VERSION 5.8 ;
BUSBITCHARS "[]" ;
DIVIDERCHAR "/" ;
UNITS
    DATABASE MICRONS 1000 ;
END UNITS

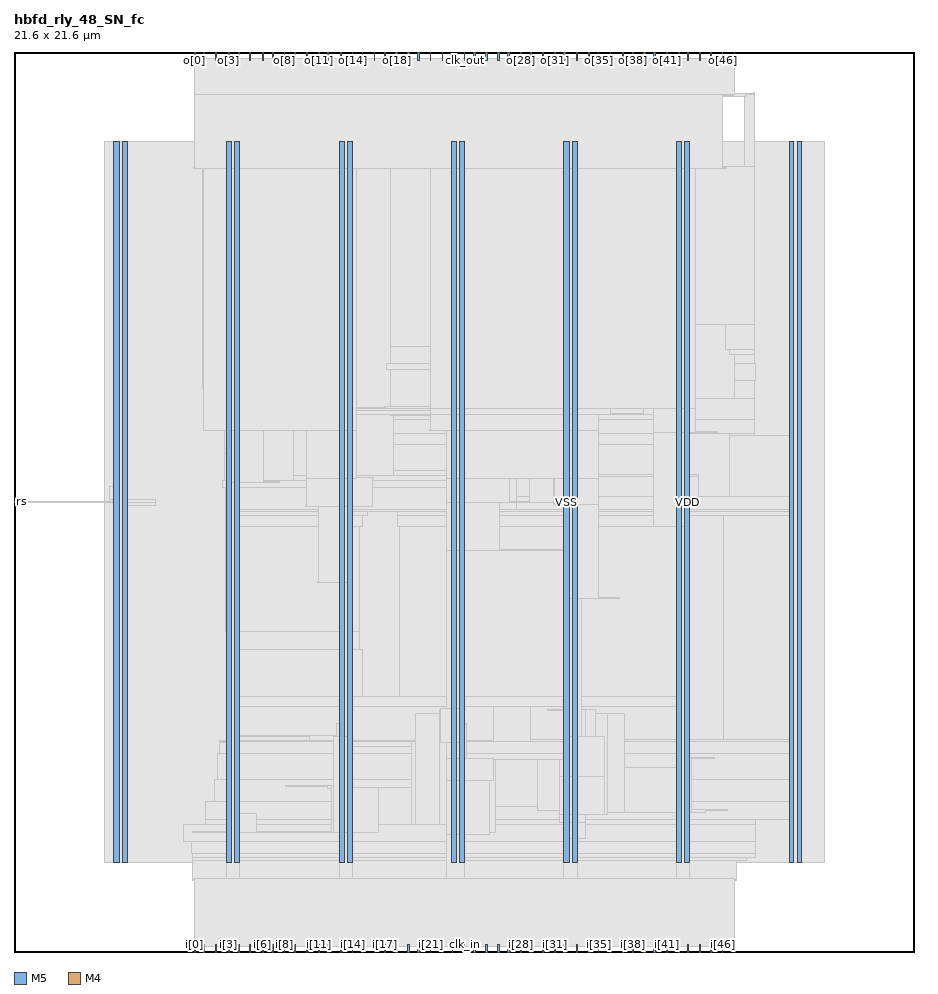
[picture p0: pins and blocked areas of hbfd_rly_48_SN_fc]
MACRO hbfd_rly_48_SN_fc
  FOREIGN hbfd_rly_48_SN_fc 0 0 ;
  CLASS BLOCK ;
  SIZE 21.6 BY 21.6 ;
  PIN clk_in
    DIRECTION INPUT ;
    USE SIGNAL ;
    PORT
      LAYER M5 ;
        RECT  10.8 0 10.824 0.192 ;
    END
  END clk_in
  PIN clk_out
    DIRECTION OUTPUT ;
    USE SIGNAL ;
    PORT
      LAYER M5 ;
        RECT  10.8 21.408 10.824 21.6 ;
    END
  END clk_out
  PIN i[0]
    DIRECTION INPUT ;
    USE SIGNAL ;
    PORT
      LAYER M5 ;
        RECT  4.32 0 4.344 0.192 ;
    END
  END i[0]
  PIN i[10]
    DIRECTION INPUT ;
    USE SIGNAL ;
    PORT
      LAYER M5 ;
        RECT  7.008 0 7.032 0.192 ;
    END
  END i[10]
  PIN i[11]
    DIRECTION INPUT ;
    USE SIGNAL ;
    PORT
      LAYER M5 ;
        RECT  7.296 0 7.32 0.192 ;
    END
  END i[11]
  PIN i[12]
    DIRECTION INPUT ;
    USE SIGNAL ;
    PORT
      LAYER M5 ;
        RECT  7.536 0 7.56 0.192 ;
    END
  END i[12]
  PIN i[13]
    DIRECTION INPUT ;
    USE SIGNAL ;
    PORT
      LAYER M5 ;
        RECT  7.824 0 7.848 0.192 ;
    END
  END i[13]
  PIN i[14]
    DIRECTION INPUT ;
    USE SIGNAL ;
    PORT
      LAYER M5 ;
        RECT  8.112 0 8.136 0.192 ;
    END
  END i[14]
  PIN i[15]
    DIRECTION INPUT ;
    USE SIGNAL ;
    PORT
      LAYER M5 ;
        RECT  8.352 0 8.376 0.192 ;
    END
  END i[15]
  PIN i[16]
    DIRECTION INPUT ;
    USE SIGNAL ;
    PORT
      LAYER M5 ;
        RECT  8.64 0 8.664 0.192 ;
    END
  END i[16]
  PIN i[17]
    DIRECTION INPUT ;
    USE SIGNAL ;
    PORT
      LAYER M5 ;
        RECT  8.88 0 8.904 0.192 ;
    END
  END i[17]
  PIN i[18]
    DIRECTION INPUT ;
    USE SIGNAL ;
    PORT
      LAYER M5 ;
        RECT  9.168 0 9.192 0.192 ;
    END
  END i[18]
  PIN i[19]
    DIRECTION INPUT ;
    USE SIGNAL ;
    PORT
      LAYER M5 ;
        RECT  9.456 0 9.48 0.192 ;
    END
  END i[19]
  PIN i[1]
    DIRECTION INPUT ;
    USE SIGNAL ;
    PORT
      LAYER M5 ;
        RECT  4.56 0 4.584 0.192 ;
    END
  END i[1]
  PIN i[20]
    DIRECTION INPUT ;
    USE SIGNAL ;
    PORT
      LAYER M5 ;
        RECT  9.696 0 9.72 0.192 ;
    END
  END i[20]
  PIN i[21]
    DIRECTION INPUT ;
    USE SIGNAL ;
    PORT
      LAYER M5 ;
        RECT  9.984 0 10.008 0.192 ;
    END
  END i[21]
  PIN i[22]
    DIRECTION INPUT ;
    USE SIGNAL ;
    PORT
      LAYER M5 ;
        RECT  10.272 0 10.296 0.192 ;
    END
  END i[22]
  PIN i[23]
    DIRECTION INPUT ;
    USE SIGNAL ;
    PORT
      LAYER M5 ;
        RECT  10.512 0 10.536 0.192 ;
    END
  END i[23]
  PIN i[24]
    DIRECTION INPUT ;
    USE SIGNAL ;
    PORT
      LAYER M5 ;
        RECT  11.04 0 11.064 0.192 ;
    END
  END i[24]
  PIN i[25]
    DIRECTION INPUT ;
    USE SIGNAL ;
    PORT
      LAYER M5 ;
        RECT  11.328 0 11.352 0.192 ;
    END
  END i[25]
  PIN i[26]
    DIRECTION INPUT ;
    USE SIGNAL ;
    PORT
      LAYER M5 ;
        RECT  11.616 0 11.64 0.192 ;
    END
  END i[26]
  PIN i[27]
    DIRECTION INPUT ;
    USE SIGNAL ;
    PORT
      LAYER M5 ;
        RECT  11.856 0 11.88 0.192 ;
    END
  END i[27]
  PIN i[28]
    DIRECTION INPUT ;
    USE SIGNAL ;
    PORT
      LAYER M5 ;
        RECT  12.144 0 12.168 0.192 ;
    END
  END i[28]
  PIN i[29]
    DIRECTION INPUT ;
    USE SIGNAL ;
    PORT
      LAYER M5 ;
        RECT  12.384 0 12.408 0.192 ;
    END
  END i[29]
  PIN i[2]
    DIRECTION INPUT ;
    USE SIGNAL ;
    PORT
      LAYER M5 ;
        RECT  4.848 0 4.872 0.192 ;
    END
  END i[2]
  PIN i[30]
    DIRECTION INPUT ;
    USE SIGNAL ;
    PORT
      LAYER M5 ;
        RECT  12.672 0 12.696 0.192 ;
    END
  END i[30]
  PIN i[31]
    DIRECTION INPUT ;
    USE SIGNAL ;
    PORT
      LAYER M5 ;
        RECT  12.96 0 12.984 0.192 ;
    END
  END i[31]
  PIN i[32]
    DIRECTION INPUT ;
    USE SIGNAL ;
    PORT
      LAYER M5 ;
        RECT  13.2 0 13.224 0.192 ;
    END
  END i[32]
  PIN i[33]
    DIRECTION INPUT ;
    USE SIGNAL ;
    PORT
      LAYER M5 ;
        RECT  13.488 0 13.512 0.192 ;
    END
  END i[33]
  PIN i[34]
    DIRECTION INPUT ;
    USE SIGNAL ;
    PORT
      LAYER M5 ;
        RECT  13.776 0 13.8 0.192 ;
    END
  END i[34]
  PIN i[35]
    DIRECTION INPUT ;
    USE SIGNAL ;
    PORT
      LAYER M5 ;
        RECT  14.016 0 14.04 0.192 ;
    END
  END i[35]
  PIN i[36]
    DIRECTION INPUT ;
    USE SIGNAL ;
    PORT
      LAYER M5 ;
        RECT  14.304 0 14.328 0.192 ;
    END
  END i[36]
  PIN i[37]
    DIRECTION INPUT ;
    USE SIGNAL ;
    PORT
      LAYER M5 ;
        RECT  14.592 0 14.616 0.192 ;
    END
  END i[37]
  PIN i[38]
    DIRECTION INPUT ;
    USE SIGNAL ;
    PORT
      LAYER M5 ;
        RECT  14.832 0 14.856 0.192 ;
    END
  END i[38]
  PIN i[39]
    DIRECTION INPUT ;
    USE SIGNAL ;
    PORT
      LAYER M5 ;
        RECT  15.12 0 15.144 0.192 ;
    END
  END i[39]
  PIN i[3]
    DIRECTION INPUT ;
    USE SIGNAL ;
    PORT
      LAYER M5 ;
        RECT  5.136 0 5.16 0.192 ;
    END
  END i[3]
  PIN i[40]
    DIRECTION INPUT ;
    USE SIGNAL ;
    PORT
      LAYER M5 ;
        RECT  15.36 0 15.384 0.192 ;
    END
  END i[40]
  PIN i[41]
    DIRECTION INPUT ;
    USE SIGNAL ;
    PORT
      LAYER M5 ;
        RECT  15.648 0 15.672 0.192 ;
    END
  END i[41]
  PIN i[42]
    DIRECTION INPUT ;
    USE SIGNAL ;
    PORT
      LAYER M5 ;
        RECT  15.936 0 15.96 0.192 ;
    END
  END i[42]
  PIN i[43]
    DIRECTION INPUT ;
    USE SIGNAL ;
    PORT
      LAYER M5 ;
        RECT  16.176 0 16.2 0.192 ;
    END
  END i[43]
  PIN i[44]
    DIRECTION INPUT ;
    USE SIGNAL ;
    PORT
      LAYER M5 ;
        RECT  16.464 0 16.488 0.192 ;
    END
  END i[44]
  PIN i[45]
    DIRECTION INPUT ;
    USE SIGNAL ;
    PORT
      LAYER M5 ;
        RECT  16.704 0 16.728 0.192 ;
    END
  END i[45]
  PIN i[46]
    DIRECTION INPUT ;
    USE SIGNAL ;
    PORT
      LAYER M5 ;
        RECT  16.992 0 17.016 0.192 ;
    END
  END i[46]
  PIN i[47]
    DIRECTION INPUT ;
    USE SIGNAL ;
    PORT
      LAYER M5 ;
        RECT  17.28 0 17.304 0.192 ;
    END
  END i[47]
  PIN i[4]
    DIRECTION INPUT ;
    USE SIGNAL ;
    PORT
      LAYER M5 ;
        RECT  5.376 0 5.4 0.192 ;
    END
  END i[4]
  PIN i[5]
    DIRECTION INPUT ;
    USE SIGNAL ;
    PORT
      LAYER M5 ;
        RECT  5.664 0 5.688 0.192 ;
    END
  END i[5]
  PIN i[6]
    DIRECTION INPUT ;
    USE SIGNAL ;
    PORT
      LAYER M5 ;
        RECT  5.952 0 5.976 0.192 ;
    END
  END i[6]
  PIN i[7]
    DIRECTION INPUT ;
    USE SIGNAL ;
    PORT
      LAYER M5 ;
        RECT  6.192 0 6.216 0.192 ;
    END
  END i[7]
  PIN i[8]
    DIRECTION INPUT ;
    USE SIGNAL ;
    PORT
      LAYER M5 ;
        RECT  6.48 0 6.504 0.192 ;
    END
  END i[8]
  PIN i[9]
    DIRECTION INPUT ;
    USE SIGNAL ;
    PORT
      LAYER M5 ;
        RECT  6.72 0 6.744 0.192 ;
    END
  END i[9]
  PIN o[0]
    DIRECTION OUTPUT ;
    USE SIGNAL ;
    PORT
      LAYER M5 ;
        RECT  4.32 21.408 4.344 21.6 ;
    END
  END o[0]
  PIN o[10]
    DIRECTION OUTPUT ;
    USE SIGNAL ;
    PORT
      LAYER M5 ;
        RECT  7.008 21.408 7.032 21.6 ;
    END
  END o[10]
  PIN o[11]
    DIRECTION OUTPUT ;
    USE SIGNAL ;
    PORT
      LAYER M5 ;
        RECT  7.296 21.408 7.32 21.6 ;
    END
  END o[11]
  PIN o[12]
    DIRECTION OUTPUT ;
    USE SIGNAL ;
    PORT
      LAYER M5 ;
        RECT  7.536 21.408 7.56 21.6 ;
    END
  END o[12]
  PIN o[13]
    DIRECTION OUTPUT ;
    USE SIGNAL ;
    PORT
      LAYER M5 ;
        RECT  7.824 21.408 7.848 21.6 ;
    END
  END o[13]
  PIN o[14]
    DIRECTION OUTPUT ;
    USE SIGNAL ;
    PORT
      LAYER M5 ;
        RECT  8.112 21.408 8.136 21.6 ;
    END
  END o[14]
  PIN o[15]
    DIRECTION OUTPUT ;
    USE SIGNAL ;
    PORT
      LAYER M5 ;
        RECT  8.352 21.408 8.376 21.6 ;
    END
  END o[15]
  PIN o[16]
    DIRECTION OUTPUT ;
    USE SIGNAL ;
    PORT
      LAYER M5 ;
        RECT  8.64 21.408 8.664 21.6 ;
    END
  END o[16]
  PIN o[17]
    DIRECTION OUTPUT ;
    USE SIGNAL ;
    PORT
      LAYER M5 ;
        RECT  8.88 21.408 8.904 21.6 ;
    END
  END o[17]
  PIN o[18]
    DIRECTION OUTPUT ;
    USE SIGNAL ;
    PORT
      LAYER M5 ;
        RECT  9.168 21.408 9.192 21.6 ;
    END
  END o[18]
  PIN o[19]
    DIRECTION OUTPUT ;
    USE SIGNAL ;
    PORT
      LAYER M5 ;
        RECT  9.456 21.408 9.48 21.6 ;
    END
  END o[19]
  PIN o[1]
    DIRECTION OUTPUT ;
    USE SIGNAL ;
    PORT
      LAYER M5 ;
        RECT  4.56 21.408 4.584 21.6 ;
    END
  END o[1]
  PIN o[20]
    DIRECTION OUTPUT ;
    USE SIGNAL ;
    PORT
      LAYER M5 ;
        RECT  9.696 21.408 9.72 21.6 ;
    END
  END o[20]
  PIN o[21]
    DIRECTION OUTPUT ;
    USE SIGNAL ;
    PORT
      LAYER M5 ;
        RECT  9.984 21.408 10.008 21.6 ;
    END
  END o[21]
  PIN o[22]
    DIRECTION OUTPUT ;
    USE SIGNAL ;
    PORT
      LAYER M5 ;
        RECT  10.272 21.408 10.296 21.6 ;
    END
  END o[22]
  PIN o[23]
    DIRECTION OUTPUT ;
    USE SIGNAL ;
    PORT
      LAYER M5 ;
        RECT  10.512 21.408 10.536 21.6 ;
    END
  END o[23]
  PIN o[24]
    DIRECTION OUTPUT ;
    USE SIGNAL ;
    PORT
      LAYER M5 ;
        RECT  11.04 21.408 11.064 21.6 ;
    END
  END o[24]
  PIN o[25]
    DIRECTION OUTPUT ;
    USE SIGNAL ;
    PORT
      LAYER M5 ;
        RECT  11.328 21.408 11.352 21.6 ;
    END
  END o[25]
  PIN o[26]
    DIRECTION OUTPUT ;
    USE SIGNAL ;
    PORT
      LAYER M5 ;
        RECT  11.616 21.408 11.64 21.6 ;
    END
  END o[26]
  PIN o[27]
    DIRECTION OUTPUT ;
    USE SIGNAL ;
    PORT
      LAYER M5 ;
        RECT  11.856 21.408 11.88 21.6 ;
    END
  END o[27]
  PIN o[28]
    DIRECTION OUTPUT ;
    USE SIGNAL ;
    PORT
      LAYER M5 ;
        RECT  12.144 21.408 12.168 21.6 ;
    END
  END o[28]
  PIN o[29]
    DIRECTION OUTPUT ;
    USE SIGNAL ;
    PORT
      LAYER M5 ;
        RECT  12.384 21.408 12.408 21.6 ;
    END
  END o[29]
  PIN o[2]
    DIRECTION OUTPUT ;
    USE SIGNAL ;
    PORT
      LAYER M5 ;
        RECT  4.848 21.408 4.872 21.6 ;
    END
  END o[2]
  PIN o[30]
    DIRECTION OUTPUT ;
    USE SIGNAL ;
    PORT
      LAYER M5 ;
        RECT  12.672 21.408 12.696 21.6 ;
    END
  END o[30]
  PIN o[31]
    DIRECTION OUTPUT ;
    USE SIGNAL ;
    PORT
      LAYER M5 ;
        RECT  12.96 21.408 12.984 21.6 ;
    END
  END o[31]
  PIN o[32]
    DIRECTION OUTPUT ;
    USE SIGNAL ;
    PORT
      LAYER M5 ;
        RECT  13.2 21.408 13.224 21.6 ;
    END
  END o[32]
  PIN o[33]
    DIRECTION OUTPUT ;
    USE SIGNAL ;
    PORT
      LAYER M5 ;
        RECT  13.488 21.408 13.512 21.6 ;
    END
  END o[33]
  PIN o[34]
    DIRECTION OUTPUT ;
    USE SIGNAL ;
    PORT
      LAYER M5 ;
        RECT  13.776 21.408 13.8 21.6 ;
    END
  END o[34]
  PIN o[35]
    DIRECTION OUTPUT ;
    USE SIGNAL ;
    PORT
      LAYER M5 ;
        RECT  14.016 21.408 14.04 21.6 ;
    END
  END o[35]
  PIN o[36]
    DIRECTION OUTPUT ;
    USE SIGNAL ;
    PORT
      LAYER M5 ;
        RECT  14.304 21.408 14.328 21.6 ;
    END
  END o[36]
  PIN o[37]
    DIRECTION OUTPUT ;
    USE SIGNAL ;
    PORT
      LAYER M5 ;
        RECT  14.592 21.408 14.616 21.6 ;
    END
  END o[37]
  PIN o[38]
    DIRECTION OUTPUT ;
    USE SIGNAL ;
    PORT
      LAYER M5 ;
        RECT  14.832 21.408 14.856 21.6 ;
    END
  END o[38]
  PIN o[39]
    DIRECTION OUTPUT ;
    USE SIGNAL ;
    PORT
      LAYER M5 ;
        RECT  15.12 21.408 15.144 21.6 ;
    END
  END o[39]
  PIN o[3]
    DIRECTION OUTPUT ;
    USE SIGNAL ;
    PORT
      LAYER M5 ;
        RECT  5.136 21.408 5.16 21.6 ;
    END
  END o[3]
  PIN o[40]
    DIRECTION OUTPUT ;
    USE SIGNAL ;
    PORT
      LAYER M5 ;
        RECT  15.36 21.408 15.384 21.6 ;
    END
  END o[40]
  PIN o[41]
    DIRECTION OUTPUT ;
    USE SIGNAL ;
    PORT
      LAYER M5 ;
        RECT  15.648 21.408 15.672 21.6 ;
    END
  END o[41]
  PIN o[42]
    DIRECTION OUTPUT ;
    USE SIGNAL ;
    PORT
      LAYER M5 ;
        RECT  15.936 21.408 15.96 21.6 ;
    END
  END o[42]
  PIN o[43]
    DIRECTION OUTPUT ;
    USE SIGNAL ;
    PORT
      LAYER M5 ;
        RECT  16.176 21.408 16.2 21.6 ;
    END
  END o[43]
  PIN o[44]
    DIRECTION OUTPUT ;
    USE SIGNAL ;
    PORT
      LAYER M5 ;
        RECT  16.464 21.408 16.488 21.6 ;
    END
  END o[44]
  PIN o[45]
    DIRECTION OUTPUT ;
    USE SIGNAL ;
    PORT
      LAYER M5 ;
        RECT  16.704 21.408 16.728 21.6 ;
    END
  END o[45]
  PIN o[46]
    DIRECTION OUTPUT ;
    USE SIGNAL ;
    PORT
      LAYER M5 ;
        RECT  16.992 21.408 17.016 21.6 ;
    END
  END o[46]
  PIN o[47]
    DIRECTION OUTPUT ;
    USE SIGNAL ;
    PORT
      LAYER M5 ;
        RECT  17.28 21.408 17.304 21.6 ;
    END
  END o[47]
  PIN o[4]
    DIRECTION OUTPUT ;
    USE SIGNAL ;
    PORT
      LAYER M5 ;
        RECT  5.376 21.408 5.4 21.6 ;
    END
  END o[4]
  PIN o[5]
    DIRECTION OUTPUT ;
    USE SIGNAL ;
    PORT
      LAYER M5 ;
        RECT  5.664 21.408 5.688 21.6 ;
    END
  END o[5]
  PIN o[6]
    DIRECTION OUTPUT ;
    USE SIGNAL ;
    PORT
      LAYER M5 ;
        RECT  5.952 21.408 5.976 21.6 ;
    END
  END o[6]
  PIN o[7]
    DIRECTION OUTPUT ;
    USE SIGNAL ;
    PORT
      LAYER M5 ;
        RECT  6.192 21.408 6.216 21.6 ;
    END
  END o[7]
  PIN o[8]
    DIRECTION OUTPUT ;
    USE SIGNAL ;
    PORT
      LAYER M5 ;
        RECT  6.48 21.408 6.504 21.6 ;
    END
  END o[8]
  PIN o[9]
    DIRECTION OUTPUT ;
    USE SIGNAL ;
    PORT
      LAYER M5 ;
        RECT  6.72 21.408 6.744 21.6 ;
    END
  END o[9]
  PIN rs
    DIRECTION INPUT ;
    USE SIGNAL ;
    PORT
      LAYER M4 ;
        RECT  0 10.8 0.192 10.824 ;
    END
  END rs
  PIN VDD
    DIRECTION INOUT ;
    USE POWER ;
    PORT
      LAYER M5 ;
        RECT  18.792 2.151 18.912 19.449 ;
        RECT  16.092 2.151 16.212 19.449 ;
        RECT  13.392 2.151 13.512 19.449 ;
        RECT  10.692 2.151 10.812 19.449 ;
        RECT  7.992 2.151 8.112 19.449 ;
        RECT  5.292 2.151 5.412 19.449 ;
        RECT  2.592 2.151 2.712 19.449 ;
    END
  END VDD
  PIN VSS
    DIRECTION INOUT ;
    USE GROUND ;
    PORT
      LAYER M5 ;
        RECT  18.6 2.137 18.72 19.463 ;
        RECT  15.9 2.137 16.02 19.463 ;
        RECT  13.2 2.137 13.32 19.463 ;
        RECT  10.5 2.137 10.62 19.463 ;
        RECT  7.8 2.137 7.92 19.463 ;
        RECT  5.1 2.137 5.22 19.463 ;
        RECT  2.4 2.137 2.52 19.463 ;
    END
  END VSS
  OBS
    LAYER RVTN ;
     RECT  2.16 2.16 19.44 2.295 ;
     RECT  2.16 2.565 19.44 2.835 ;
     RECT  2.16 3.105 19.44 3.375 ;
     RECT  2.16 3.645 19.44 3.915 ;
     RECT  2.16 4.185 19.44 4.455 ;
     RECT  2.16 4.725 19.44 4.995 ;
     RECT  2.16 5.265 19.44 5.535 ;
     RECT  2.16 5.805 19.44 6.075 ;
     RECT  2.16 6.345 19.44 6.615 ;
     RECT  2.16 6.885 19.44 7.155 ;
     RECT  2.16 7.425 19.44 7.695 ;
     RECT  2.16 7.965 19.44 8.235 ;
     RECT  2.16 8.505 19.44 8.775 ;
     RECT  2.16 9.045 19.44 9.315 ;
     RECT  2.16 9.585 19.44 9.855 ;
     RECT  2.16 10.125 19.44 10.395 ;
     RECT  2.16 10.665 19.44 10.935 ;
     RECT  2.16 11.205 19.44 11.475 ;
     RECT  2.16 11.745 19.44 12.015 ;
     RECT  2.16 12.285 19.44 12.555 ;
     RECT  2.16 12.825 19.44 13.095 ;
     RECT  2.16 13.365 19.44 13.635 ;
     RECT  2.16 13.905 19.44 14.175 ;
     RECT  2.16 14.445 19.44 14.715 ;
     RECT  2.16 14.985 19.44 15.255 ;
     RECT  2.16 15.525 19.44 15.795 ;
     RECT  2.16 16.065 19.44 16.335 ;
     RECT  2.16 16.605 19.44 16.875 ;
     RECT  2.16 17.145 19.44 17.415 ;
     RECT  2.16 17.685 19.44 17.955 ;
     RECT  2.16 18.225 19.44 18.495 ;
     RECT  2.16 18.765 19.44 19.035 ;
     RECT  2.16 19.305 19.44 19.44 ;
    LAYER RVTP ;
     RECT  2.16 2.295 19.44 2.565 ;
     RECT  2.16 2.835 19.44 3.105 ;
     RECT  2.16 3.375 19.44 3.645 ;
     RECT  2.16 3.915 19.44 4.185 ;
     RECT  2.16 4.455 19.44 4.725 ;
     RECT  2.16 4.995 19.44 5.265 ;
     RECT  2.16 5.535 19.44 5.805 ;
     RECT  2.16 6.075 19.44 6.345 ;
     RECT  2.16 6.615 19.44 6.885 ;
     RECT  2.16 7.155 19.44 7.425 ;
     RECT  2.16 7.695 19.44 7.965 ;
     RECT  2.16 8.235 19.44 8.505 ;
     RECT  2.16 8.775 19.44 9.045 ;
     RECT  2.16 9.315 19.44 9.585 ;
     RECT  2.16 9.855 19.44 10.125 ;
     RECT  2.16 10.395 19.44 10.665 ;
     RECT  2.16 10.935 19.44 11.205 ;
     RECT  2.16 11.475 19.44 11.745 ;
     RECT  2.16 12.015 19.44 12.285 ;
     RECT  2.16 12.555 19.44 12.825 ;
     RECT  2.16 13.095 19.44 13.365 ;
     RECT  2.16 13.635 19.44 13.905 ;
     RECT  2.16 14.175 19.44 14.445 ;
     RECT  2.16 14.715 19.44 14.985 ;
     RECT  2.16 15.255 19.44 15.525 ;
     RECT  2.16 15.795 19.44 16.065 ;
     RECT  2.16 16.335 19.44 16.605 ;
     RECT  2.16 16.875 19.44 17.145 ;
     RECT  2.16 17.415 19.44 17.685 ;
     RECT  2.16 17.955 19.44 18.225 ;
     RECT  2.16 18.495 19.44 18.765 ;
     RECT  2.16 19.035 19.44 19.305 ;
    LAYER M1 ;
     RECT  2.16 2.151 19.44 19.449 ;
    LAYER M2 ;
     RECT  2.16 2.151 19.44 19.449 ;
    LAYER M3 ;
     RECT  4.284 1.723 17.334 2.191 ;
     RECT  4.284 2.191 17.586 2.263 ;
     RECT  4.284 2.263 17.802 2.371 ;
     RECT  2.415 2.143 2.505 2.413 ;
     RECT  18.615 2.143 18.705 2.413 ;
     RECT  4.248 2.371 17.802 2.641 ;
     RECT  4.068 2.641 17.802 3.065 ;
     RECT  4.608 3.065 17.802 3.181 ;
     RECT  18.615 2.413 18.897 3.181 ;
     RECT  4.608 3.181 18.897 3.605 ;
     RECT  4.824 3.605 18.897 4.145 ;
     RECT  4.896 4.145 18.897 4.757 ;
     RECT  4.932 4.757 18.897 5.063 ;
     RECT  4.932 5.063 11.502 5.069 ;
     RECT  12.384 5.063 18.897 5.099 ;
     RECT  5.115 5.069 11.502 5.881 ;
     RECT  12.384 5.099 16.197 5.881 ;
     RECT  5.115 5.881 16.197 6.143 ;
     RECT  5.115 6.143 8.37 7.259 ;
     RECT  5.115 7.259 8.298 7.699 ;
     RECT  5.076 7.699 8.298 10.201 ;
     RECT  9.252 6.143 16.197 10.201 ;
     RECT  5.076 10.201 8.37 10.471 ;
     RECT  9.216 10.201 16.197 10.471 ;
     RECT  17.028 5.099 18.897 10.471 ;
     RECT  5.076 10.471 8.478 10.561 ;
     RECT  9.216 10.471 18.897 10.561 ;
     RECT  5.076 10.561 18.897 10.625 ;
     RECT  2.415 2.413 2.697 10.705 ;
     RECT  2.415 10.705 3.402 10.795 ;
     RECT  2.304 10.795 3.402 10.859 ;
     RECT  12.06 10.625 18.897 10.931 ;
     RECT  5.076 10.625 11.322 11.137 ;
     RECT  2.304 10.859 2.697 11.165 ;
     RECT  5.004 11.137 11.322 11.309 ;
     RECT  12.06 10.931 16.434 11.405 ;
     RECT  6.696 11.309 11.322 11.435 ;
     RECT  13.215 11.405 16.434 11.471 ;
     RECT  9.108 11.435 11.322 11.551 ;
     RECT  12.06 11.405 12.222 11.551 ;
     RECT  5.04 11.309 5.85 11.975 ;
     RECT  9.108 11.551 12.222 12.181 ;
     RECT  13.215 11.471 16.197 12.181 ;
     RECT  17.172 10.931 18.897 12.389 ;
     RECT  9.108 12.181 16.197 12.451 ;
     RECT  17.172 12.389 17.766 12.451 ;
     RECT  6.696 11.435 8.097 12.631 ;
     RECT  5.04 11.975 5.778 12.721 ;
     RECT  9.108 12.451 17.766 12.785 ;
     RECT  9.108 12.785 12.294 12.865 ;
     RECT  6.696 12.631 8.154 12.901 ;
     RECT  9.036 12.865 12.294 12.901 ;
     RECT  5.04 12.721 5.922 12.991 ;
     RECT  6.696 12.901 12.294 12.991 ;
     RECT  5.04 12.991 12.294 13.055 ;
     RECT  8.892 13.055 12.294 13.085 ;
     RECT  5.04 13.055 8.097 13.091 ;
     RECT  13.176 12.785 17.766 13.289 ;
     RECT  5.04 13.091 5.778 13.441 ;
     RECT  13.176 13.289 16.326 13.469 ;
     RECT  4.932 13.441 5.778 13.531 ;
     RECT  13.176 13.469 16.254 13.595 ;
     RECT  4.536 13.531 5.778 13.631 ;
     RECT  17.28 13.289 17.766 13.711 ;
     RECT  13.176 13.595 14.238 13.937 ;
     RECT  9.036 13.085 12.294 13.981 ;
     RECT  14.976 13.595 16.254 14.045 ;
     RECT  8.928 13.981 12.294 14.135 ;
     RECT  17.28 13.711 17.802 14.135 ;
     RECT  6.732 13.091 8.097 14.171 ;
     RECT  15.876 14.045 16.254 14.243 ;
     RECT  17.28 14.135 17.766 14.341 ;
     RECT  17.172 14.341 17.766 14.449 ;
     RECT  9.036 14.135 12.294 14.521 ;
     RECT  13.176 13.937 14.094 14.521 ;
     RECT  4.536 13.631 5.742 15.061 ;
     RECT  15.876 14.243 16.197 15.061 ;
     RECT  17.064 14.449 17.766 15.061 ;
     RECT  4.536 15.061 5.778 15.389 ;
     RECT  9.036 14.521 14.094 18.797 ;
     RECT  4.536 15.389 5.634 18.845 ;
     RECT  9.036 18.797 12.294 18.845 ;
     RECT  15.876 15.061 17.766 18.845 ;
     RECT  2.415 11.165 2.697 19.187 ;
     RECT  7.776 14.171 8.097 19.187 ;
     RECT  13.176 18.797 14.094 19.187 ;
     RECT  15.876 18.845 16.197 19.187 ;
     RECT  18.615 12.389 18.897 19.187 ;
     RECT  2.415 19.187 2.505 19.457 ;
     RECT  7.776 19.187 7.905 19.457 ;
     RECT  10.515 18.845 12.294 19.457 ;
     RECT  13.176 19.187 13.305 19.457 ;
     RECT  15.876 19.187 16.005 19.457 ;
     RECT  18.615 19.187 18.705 19.457 ;
     RECT  15.876 19.457 15.894 19.613 ;
     RECT  5.04 18.845 5.634 20.573 ;
     RECT  6.732 14.171 6.75 20.573 ;
     RECT  7.776 19.457 7.794 20.573 ;
     RECT  9.036 18.845 9.774 20.573 ;
     RECT  10.656 19.457 12.294 20.573 ;
     RECT  13.176 19.457 13.194 20.573 ;
     RECT  14.076 19.187 14.094 20.573 ;
     RECT  14.976 14.045 14.994 20.573 ;
     RECT  17.532 18.845 17.766 20.573 ;
     RECT  9.252 20.573 9.774 20.621 ;
     RECT  11.16 20.573 11.178 20.621 ;
     RECT  17.748 20.573 17.766 20.621 ;
    LAYER M4 ;
     RECT  0.156 10.8 2.408 10.824 ;
     RECT  2.408 2.148 2.512 19.452 ;
     RECT  2.512 2.418 2.704 19.182 ;
     RECT  4.273 1.728 5.108 1.752 ;
     RECT  4.273 2.88 5.108 2.904 ;
     RECT  4.921 5.04 5.108 5.064 ;
     RECT  4.549 12.528 5.108 12.552 ;
     RECT  4.309 18.816 5.108 18.84 ;
     RECT  5.108 1.728 5.365 19.452 ;
     RECT  5.365 1.728 5.404 19.56 ;
     RECT  5.404 17.088 5.555 17.112 ;
     RECT  5.404 19.536 5.555 19.56 ;
     RECT  5.404 15.36 5.789 15.384 ;
     RECT  5.404 2.88 5.825 3.336 ;
     RECT  5.404 11.28 6.365 11.304 ;
     RECT  5.404 12.528 6.709 12.552 ;
     RECT  5.404 5.184 7.081 5.208 ;
     RECT  6.505 3.984 7.513 4.008 ;
     RECT  5.825 2.88 7.628 2.904 ;
     RECT  7.513 3.936 7.628 4.008 ;
     RECT  6.709 12.528 7.669 13.032 ;
     RECT  4.837 20.544 7.669 20.568 ;
     RECT  7.081 5.088 7.729 5.208 ;
     RECT  5.404 1.728 7.808 1.752 ;
     RECT  7.628 2.88 7.808 4.008 ;
     RECT  7.729 5.088 7.808 5.496 ;
     RECT  7.285 8.88 7.808 8.904 ;
     RECT  6.997 10.704 7.808 10.728 ;
     RECT  7.669 12.528 7.808 13.08 ;
     RECT  7.669 19.584 7.808 20.568 ;
     RECT  7.808 1.728 7.859 20.568 ;
     RECT  7.859 1.728 8.104 19.56 ;
     RECT  8.104 18.816 8.243 19.56 ;
     RECT  8.104 10.704 8.597 11.4 ;
     RECT  7.859 20.544 8.629 20.568 ;
     RECT  8.597 11.376 8.633 11.4 ;
     RECT  8.104 2.88 8.741 3.96 ;
     RECT  8.104 13.056 8.921 13.08 ;
     RECT  8.741 3.072 9.529 3.96 ;
     RECT  8.104 4.944 9.529 5.064 ;
     RECT  9.529 3.072 9.637 5.064 ;
     RECT  9.637 3.072 10.213 5.736 ;
     RECT  8.243 18.816 10.357 18.84 ;
     RECT  8.104 1.728 10.508 1.752 ;
     RECT  10.213 3.072 10.508 5.832 ;
     RECT  9.973 12.528 10.508 12.552 ;
     RECT  10.357 18.816 10.508 19.56 ;
     RECT  10.508 1.728 10.804 19.56 ;
     RECT  10.357 0.192 10.835 0.216 ;
     RECT  10.804 19.536 10.835 19.56 ;
     RECT  10.804 2.832 10.865 5.496 ;
     RECT  8.629 20.544 11.189 20.616 ;
     RECT  10.865 2.832 11.411 4.632 ;
     RECT  11.411 2.88 11.549 4.632 ;
     RECT  10.804 12.528 11.621 12.552 ;
     RECT  10.804 13.632 11.621 13.656 ;
     RECT  11.845 10.8 12.373 10.824 ;
     RECT  11.549 3.504 12.553 4.632 ;
     RECT  12.373 10.8 12.949 11.4 ;
     RECT  12.553 3.408 13.093 4.632 ;
     RECT  10.804 1.728 13.208 1.752 ;
     RECT  13.093 3.12 13.208 4.632 ;
     RECT  12.805 5.808 13.208 5.832 ;
     RECT  10.804 9.648 13.208 9.672 ;
     RECT  12.949 10.752 13.208 11.4 ;
     RECT  12.661 18.768 13.208 18.792 ;
     RECT  13.208 1.728 13.477 19.452 ;
     RECT  13.477 1.728 13.504 19.56 ;
     RECT  13.504 12 13.619 12.936 ;
     RECT  13.504 17.664 13.619 17.688 ;
     RECT  13.504 19.536 13.619 19.56 ;
     RECT  13.504 2.736 13.715 5.832 ;
     RECT  13.715 3.312 13.961 5.832 ;
     RECT  13.961 3.312 14.236 5.736 ;
     RECT  13.504 8.496 14.537 8.52 ;
     RECT  14.236 3.36 14.645 5.736 ;
     RECT  11.189 20.544 15.005 20.568 ;
     RECT  13.619 12.912 15.109 12.936 ;
     RECT  14.581 14.016 15.109 14.04 ;
     RECT  14.645 3.36 15.901 4.44 ;
     RECT  13.504 1.728 15.908 1.752 ;
     RECT  15.901 3.36 15.908 4.68 ;
     RECT  15.349 10.224 15.908 10.248 ;
     RECT  15.637 11.232 15.908 11.256 ;
     RECT  15.109 12.912 15.908 14.04 ;
     RECT  15.865 19.584 15.908 19.608 ;
     RECT  15.908 1.728 15.971 19.608 ;
     RECT  15.971 1.728 16.204 19.56 ;
     RECT  16.204 3.36 16.265 4.68 ;
     RECT  16.204 18.816 16.355 19.56 ;
     RECT  16.265 3.36 16.589 3.432 ;
     RECT  16.265 4.656 16.805 4.68 ;
     RECT  16.204 12.48 16.877 12.504 ;
     RECT  16.355 18.816 17.093 18.84 ;
     RECT  16.589 3.408 17.129 3.432 ;
     RECT  16.693 20.544 17.269 20.568 ;
     RECT  16.204 1.728 17.345 1.752 ;
     RECT  17.269 20.544 17.561 20.616 ;
     RECT  17.561 20.592 17.777 20.616 ;
     RECT  18.608 2.148 18.712 19.452 ;
     RECT  18.712 2.418 18.904 19.182 ;
    LAYER M5 ;
     RECT  4.32 0.144 17.304 1.763 ;
     RECT  2.4 2.137 2.52 2.151 ;
     RECT  18.6 2.137 18.72 2.151 ;
     RECT  13.2 1.763 13.512 2.725 ;
     RECT  10.368 1.763 10.812 2.821 ;
     RECT  7.8 1.763 8.112 2.869 ;
     RECT  13.2 2.725 13.704 3.109 ;
     RECT  13.104 3.109 13.704 3.301 ;
     RECT  10.368 2.821 11.4 4.117 ;
     RECT  13.104 3.301 14.184 4.211 ;
     RECT  10.368 4.117 11.496 4.643 ;
     RECT  10.368 4.643 10.812 5.029 ;
     RECT  7.68 2.869 8.112 5.171 ;
     RECT  13.2 4.211 14.184 5.171 ;
     RECT  10.224 5.029 10.812 5.843 ;
     RECT  13.2 5.171 13.608 8.485 ;
     RECT  7.8 5.171 8.112 8.869 ;
     RECT  10.368 5.843 10.812 9.637 ;
     RECT  15.9 1.763 16.212 10.213 ;
     RECT  7.296 8.869 8.112 10.693 ;
     RECT  13.2 8.485 14.04 10.741 ;
     RECT  10.368 9.637 11.64 10.789 ;
     RECT  5.1 1.763 5.412 11.269 ;
     RECT  7.008 10.693 8.112 11.365 ;
     RECT  10.368 10.789 11.88 11.365 ;
     RECT  12.96 10.741 14.04 11.365 ;
     RECT  15.36 10.213 16.212 12.469 ;
     RECT  5.1 11.269 5.976 12.517 ;
     RECT  7.008 11.365 8.232 12.517 ;
     RECT  10.368 11.365 14.04 12.517 ;
     RECT  9.984 12.517 14.04 12.901 ;
     RECT  9.984 12.901 14.328 13.045 ;
     RECT  15.36 12.469 16.344 13.045 ;
     RECT  4.56 12.517 8.232 18.805 ;
     RECT  9.984 13.045 16.344 18.805 ;
     RECT  2.4 2.151 2.712 19.449 ;
     RECT  18.6 2.151 18.912 19.449 ;
     RECT  2.4 19.449 2.52 19.463 ;
     RECT  18.6 19.449 18.72 19.463 ;
     RECT  4.32 18.805 17.016 20.581 ;
     RECT  4.32 20.581 17.304 21.456 ;
  END
END hbfd_rly_48_SN_fc
END LIBRARY
